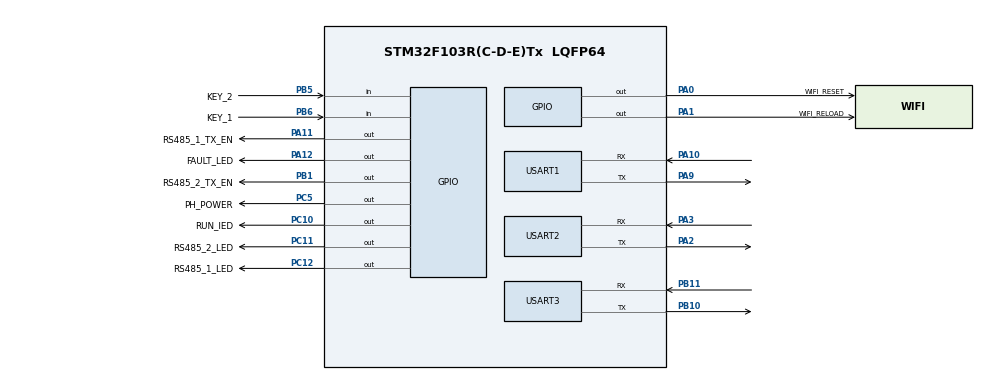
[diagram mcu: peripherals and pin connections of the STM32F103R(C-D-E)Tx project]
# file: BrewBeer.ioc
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Dma.Request0=USART1_RX
Dma.Request1=USART1_TX
Dma.Request2=USART3_RX
Dma.Request3=USART3_TX
Dma.Request4=USART2_RX
Dma.Request5=USART2_TX
Dma.USART1_RX.0.Direction=DMA_PERIPH_TO_MEMORY
Dma.USART1_RX.0.Instance=DMA1_Channel5
Dma.USART1_RX.0.MemDataAlignment=DMA_MDATAALIGN_BYTE
Dma.USART1_RX.0.MemInc=DMA_MINC_ENABLE
Dma.USART1_RX.0.Mode=DMA_NORMAL
Dma.USART1_RX.0.PeriphDataAlignment=DMA_PDATAALIGN_BYTE
Dma.USART1_RX.0.PeriphInc=DMA_PINC_DISABLE
Dma.USART1_RX.0.Priority=DMA_PRIORITY_HIGH
Dma.USART1_TX.1.Direction=DMA_MEMORY_TO_PERIPH
Dma.USART1_TX.1.Instance=DMA1_Channel4
Dma.USART1_TX.1.MemDataAlignment=DMA_MDATAALIGN_BYTE
Dma.USART1_TX.1.MemInc=DMA_MINC_ENABLE
Dma.USART1_TX.1.Mode=DMA_NORMAL
Dma.USART1_TX.1.PeriphDataAlignment=DMA_PDATAALIGN_BYTE
Dma.USART1_TX.1.PeriphInc=DMA_PINC_DISABLE
Dma.USART1_TX.1.Priority=DMA_PRIORITY_LOW
Dma.USART2_RX.4.Direction=DMA_PERIPH_TO_MEMORY
Dma.USART2_RX.4.Instance=DMA1_Channel6
Dma.USART2_RX.4.MemDataAlignment=DMA_MDATAALIGN_BYTE
Dma.USART2_RX.4.MemInc=DMA_MINC_ENABLE
Dma.USART2_RX.4.Mode=DMA_NORMAL
Dma.USART2_RX.4.PeriphDataAlignment=DMA_PDATAALIGN_BYTE
Dma.USART2_RX.4.PeriphInc=DMA_PINC_DISABLE
Dma.USART2_RX.4.Priority=DMA_PRIORITY_HIGH
Dma.USART2_TX.5.Direction=DMA_MEMORY_TO_PERIPH
Dma.USART2_TX.5.Instance=DMA1_Channel7
Dma.USART2_TX.5.MemDataAlignment=DMA_MDATAALIGN_BYTE
Dma.USART2_TX.5.MemInc=DMA_MINC_ENABLE
Dma.USART2_TX.5.Mode=DMA_NORMAL
Dma.USART2_TX.5.PeriphDataAlignment=DMA_PDATAALIGN_BYTE
Dma.USART2_TX.5.PeriphInc=DMA_PINC_DISABLE
Dma.USART2_TX.5.Priority=DMA_PRIORITY_LOW
Dma.USART3_RX.2.Direction=DMA_PERIPH_TO_MEMORY
Dma.USART3_RX.2.Instance=DMA1_Channel3
Dma.USART3_RX.2.MemDataAlignment=DMA_MDATAALIGN_BYTE
Dma.USART3_RX.2.MemInc=DMA_MINC_ENABLE
Dma.USART3_RX.2.Mode=DMA_NORMAL
Dma.USART3_RX.2.PeriphDataAlignment=DMA_PDATAALIGN_BYTE
Dma.USART3_RX.2.PeriphInc=DMA_PINC_DISABLE
Dma.USART3_RX.2.Priority=DMA_PRIORITY_HIGH
Dma.USART3_TX.3.Direction=DMA_MEMORY_TO_PERIPH
Dma.USART3_TX.3.Instance=DMA1_Channel2
Dma.USART3_TX.3.MemDataAlignment=DMA_MDATAALIGN_BYTE
Dma.USART3_TX.3.MemInc=DMA_MINC_ENABLE
Dma.USART3_TX.3.Mode=DMA_NORMAL
Dma.USART3_TX.3.PeriphDataAlignment=DMA_PDATAALIGN_BYTE
Dma.USART3_TX.3.PeriphInc=DMA_PINC_DISABLE
Dma.USART3_TX.3.Priority=DMA_PRIORITY_LOW
FREERTOS.INCLUDE_uxTaskGetStackHighWaterMark=1
FREERTOS.INCLUDE_xTaskGetCurrentTaskHandle=1
FREERTOS.Queues01=SerialQueue,5,uint32_t,NULL;KeyQueue,4,uint8_t,NULL;SysQueue,8,uint32_t,NULL
FREERTOS.Tasks01=System,0,200,SystemTask,Default;SerialServer,2,300,SerialServerTask,Default;ReadKey,0,128,ReadKeyTask,Default;DealKey,1,200,DealKeyTask,Default;Watcher,0,400,WatcherTask,Default
FREERTOS.configTOTAL_HEAP_SIZE=20480
FREERTOS.configUSE_IDLE_HOOK=1
FREERTOS.configUSE_TICK_HOOK=1
IWDG.Prescaler=IWDG_PRESCALER_64
Mcu.Family=STM32F1
Mcu.Name=STM32F103R(C-D-E)Tx
Mcu.Package=LQFP64
NVIC.DMA1_Channel2_IRQn=true\:5\:0\:true\:false\:true\:true
NVIC.DMA1_Channel3_IRQn=true\:5\:0\:false\:false\:true\:true
NVIC.DMA1_Channel4_IRQn=true\:5\:0\:false\:false\:true\:true
NVIC.DMA1_Channel5_IRQn=true\:5\:0\:false\:false\:true\:true
NVIC.DMA1_Channel6_IRQn=true\:5\:0\:false\:false\:true\:true
NVIC.DMA1_Channel7_IRQn=true\:5\:0\:false\:false\:true\:true
NVIC.PriorityGroup=NVIC_PRIORITYGROUP_4
NVIC.TIM1_UP_IRQn=true\:8\:0\:true\:false\:true\:true
NVIC.TIM2_IRQn=true\:8\:0\:true\:false\:true\:true
NVIC.TIM3_IRQn=true\:8\:0\:true\:false\:true\:true
NVIC.TIM4_IRQn=true\:8\:0\:true\:false\:true\:true
NVIC.TIM5_IRQn=true\:8\:0\:true\:false\:true\:true
NVIC.TIM6_IRQn=true\:8\:0\:true\:false\:true\:true
NVIC.TIM7_IRQn=true\:0\:0\:false\:false\:true\:false
NVIC.TimeBase=TIM7_IRQn
NVIC.TimeBaseIP=TIM7
NVIC.USART1_IRQn=true\:5\:0\:true\:false\:true\:true
NVIC.USART2_IRQn=true\:5\:0\:false\:false\:true\:true
NVIC.USART3_IRQn=true\:5\:0\:false\:false\:true\:true
PA0-WKUP.GPIO_Label=WIFI_RESET
PA0-WKUP.Signal=GPIO_Output
PA1.GPIO_Label=WIFI_RELOAD
PA1.Signal=GPIO_Output
PA10.Mode=Asynchronous
PA10.Signal=USART1_RX
PA11.GPIO_Label=RS485_1_TX_EN
PA11.Signal=GPIO_Output
PA12.GPIO_Label=FAULT_LED
PA12.Signal=GPIO_Output
PA13.Mode=Serial_Wire
PA13.Signal=SYS_JTMS-SWDIO
PA14.Mode=Serial_Wire
PA14.Signal=SYS_JTCK-SWCLK
PA2.Mode=Asynchronous
PA2.Signal=USART2_TX
PA3.Mode=Asynchronous
PA3.Signal=USART2_RX
PA9.Mode=Asynchronous
PA9.Signal=USART1_TX
PB1.GPIO_Label=RS485_2_TX_EN
PB1.Signal=GPIO_Output
PB10.Mode=Asynchronous
PB10.Signal=USART3_TX
PB11.Mode=Asynchronous
PB11.Signal=USART3_RX
PB5.GPIO_Label=KEY_2
PB5.Signal=GPIO_Input
PB6.GPIO_Label=KEY_1
PB6.Signal=GPIO_Input
PC10.GPIO_Label=RUN_IED
PC10.Signal=GPIO_Output
PC11.GPIO_Label=RS485_2_LED
PC11.Signal=GPIO_Output
PC12.GPIO_Label=RS485_1_LED
PC12.Signal=GPIO_Output
PC14-OSC32_IN.Mode=LSE-External-Oscillator
PC14-OSC32_IN.Signal=RCC_OSC32_IN
PC15-OSC32_OUT.Mode=LSE-External-Oscillator
PC15-OSC32_OUT.Signal=RCC_OSC32_OUT
PC5.GPIO_Label=PH_POWER
PC5.Signal=GPIO_Output
PD0-OSC_IN.Mode=HSE-External-Oscillator
PD0-OSC_IN.Signal=RCC_OSC_IN
PD1-OSC_OUT.Mode=HSE-External-Oscillator
PD1-OSC_OUT.Signal=RCC_OSC_OUT
ProjectManager.HeapSize=0x800
ProjectManager.StackSize=0x800
ProjectManager.TargetToolchain=MDK-ARM V5
RCC.AHBFreq_Value=72000000
RCC.APB1CLKDivider=RCC_HCLK_DIV2
RCC.APB1Freq_Value=36000000
RCC.APB1TimFreq_Value=72000000
RCC.APB2Freq_Value=72000000
RCC.APB2TimFreq_Value=72000000
RCC.HCLKFreq_Value=72000000
RCC.HSIState=RCC_HSI_ON
RCC.PLLMUL=RCC_PLL_MUL9
RCC.PLLSourceVirtual=RCC_PLLSOURCE_HSE
RCC.RTCClockSelection=RCC_RTCCLKSOURCE_LSE
RCC.SYSCLKFreq_VALUE=72000000
RCC.SYSCLKSource=RCC_SYSCLKSOURCE_PLLCLK
RCC.USBFreq_Value=72000000
TIM1.Period=999
TIM1.Prescaler=71
TIM2.Period=999
TIM2.Prescaler=71
TIM3.Period=999
TIM3.Prescaler=71
TIM4.Period=999
TIM4.Prescaler=71
TIM5.Period=999
TIM5.Prescaler=71
TIM6.Period=999
TIM6.Prescaler=71
VP_FREERTOS_VS_ENABLE.Mode=Enabled
VP_IWDG_VS_IWDG.Mode=IWDG_Activate
VP_RTC_No_RTC_Output.Mode=RTC_OUT_NO
VP_SYS_VS_tim7.Mode=TIM7
VP_TIM1_VS_ClockSourceINT.Mode=Internal
VP_TIM2_VS_ClockSourceINT.Mode=Internal
VP_TIM3_VS_ClockSourceINT.Mode=Internal
VP_TIM4_VS_ClockSourceINT.Mode=Internal
VP_TIM5_VS_ClockSourceINT.Mode=Internal
VP_TIM6_VS_ClockSourceINT.Mode=Enable_Timer
board=BrewBeer

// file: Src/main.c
/**
  ******************************************************************************
  * File Name          : main.c
  * Description        : Main program body
  ******************************************************************************
  *
  * COPYRIGHT(c) 2017 STMicroelectronics
  *
  * Redistribution and use in source and binary forms, with or without modification,
  * are permitted provided that the following conditions are met:
  *   1. Redistributions of source code must retain the above copyright notice,
  *      this list of conditions and the following disclaimer.
  *   2. Redistributions in binary form must reproduce the above copyright notice,
  *      this list of conditions and the following disclaimer in the documentation
  *      and/or other materials provided with the distribution.
  *   3. Neither the name of STMicroelectronics nor the names of its contributors
  *      may be used to endorse or promote products derived from this software
  *      without specific prior written permission.
  *
  * THIS SOFTWARE IS PROVIDED BY THE COPYRIGHT HOLDERS AND CONTRIBUTORS "AS IS"
  * AND ANY EXPRESS OR IMPLIED WARRANTIES, INCLUDING, BUT NOT LIMITED TO, THE
  * IMPLIED WARRANTIES OF MERCHANTABILITY AND FITNESS FOR A PARTICULAR PURPOSE ARE
  * DISCLAIMED. IN NO EVENT SHALL THE COPYRIGHT HOLDER OR CONTRIBUTORS BE LIABLE
  * FOR ANY DIRECT, INDIRECT, INCIDENTAL, SPECIAL, EXEMPLARY, OR CONSEQUENTIAL
  * DAMAGES (INCLUDING, BUT NOT LIMITED TO, PROCUREMENT OF SUBSTITUTE GOODS OR
  * SERVICES; LOSS OF USE, DATA, OR PROFITS; OR BUSINESS INTERRUPTION) HOWEVER
  * CAUSED AND ON ANY THEORY OF LIABILITY, WHETHER IN CONTRACT, STRICT LIABILITY,
  * OR TORT (INCLUDING NEGLIGENCE OR OTHERWISE) ARISING IN ANY WAY OUT OF THE USE
  * OF THIS SOFTWARE, EVEN IF ADVISED OF THE POSSIBILITY OF SUCH DAMAGE.
  *
  ******************************************************************************
  */
#include "stm32f1xx_hal.h"
#include "cmsis_os.h"
#include "dma.h"
#include "iwdg.h"
#include "rtc.h"
#include "tim.h"
#include "usart.h"
#include "gpio.h"

/* USER CODE BEGIN Includes */
#include "include.h"
/* USER CODE END Includes */

/* USER CODE BEGIN PV */
/* Private variables ---------------------------------------------------------*/

/* USER CODE END PV */

void SystemClock_Config(void);
void Error_Handler(void);
void MX_FREERTOS_Init(void);

/* USER CODE BEGIN PFP */
/* Private function prototypes -----------------------------------------------*/

/* USER CODE END PFP */

int main(void)
{

  /* USER CODE BEGIN 1 */

	start_app();
  while(1);
  /* USER CODE END 1 */

  /* MCU Configuration----------------------------------------------------------*/

  /* Reset of all peripherals, Initializes the Flash interface and the Systick. */
  HAL_Init();

  /* Configure the system clock */
  SystemClock_Config();

  /* Initialize all configured peripherals */
  MX_GPIO_Init();
  MX_DMA_Init();
  MX_RTC_Init();
  MX_USART1_UART_Init();
  MX_USART2_UART_Init();
  MX_IWDG_Init();
  MX_TIM1_Init();
  MX_TIM2_Init();
  MX_TIM3_Init();
  MX_TIM4_Init();
  MX_TIM5_Init();
  MX_TIM6_Init();
  MX_USART3_UART_Init();

  /* USER CODE BEGIN 2 */

  	PH_POWER_ON;
  	ENABLE_RS485_1_RX;
  	ENABLE_RS485_2_RX;

  	RELEASE_SMART_LINK;
  	RELEASE_WIFI_RESET;

	//SET_SMART_LINK;
	InitSoftTimer();
  	COM1LedBlink(500,0);
  	COM2LedBlink(400,0);
  	RuningLedBlink(300,0);
  	FaultLedBlink(100,0);
	SetAutoUpload(MachineInfo.UploadStepTime);//设置定时上传
	HAL_IWDG_Start(&hiwdg);
  /* USER CODE END 2 */

  /* Call init function for freertos objects (in freertos.c) */
  MX_FREERTOS_Init();

  /* Start scheduler */
  osKernelStart();

  /* We should never get here as control is now taken by the scheduler */

  /* Infinite loop */
  while (1)
  {

  }

}

/** System Clock Configuration
*/
void SystemClock_Config(void)
{

  RCC_OscInitTypeDef RCC_OscInitStruct;
  RCC_ClkInitTypeDef RCC_ClkInitStruct;
  RCC_PeriphCLKInitTypeDef PeriphClkInit;

  RCC_OscInitStruct.OscillatorType = RCC_OSCILLATORTYPE_LSI|RCC_OSCILLATORTYPE_HSE
                              |RCC_OSCILLATORTYPE_LSE;
  RCC_OscInitStruct.HSEState = RCC_HSE_ON;
  RCC_OscInitStruct.HSEPredivValue = RCC_HSE_PREDIV_DIV1;
  RCC_OscInitStruct.LSEState = RCC_LSE_ON;
  RCC_OscInitStruct.LSIState = RCC_LSI_ON;
  RCC_OscInitStruct.PLL.PLLState = RCC_PLL_ON;
  RCC_OscInitStruct.PLL.PLLSource = RCC_PLLSOURCE_HSE;
  RCC_OscInitStruct.PLL.PLLMUL = RCC_PLL_MUL9;
  if (HAL_RCC_OscConfig(&RCC_OscInitStruct) != HAL_OK)
  {
    Error_Handler();
  }

  RCC_ClkInitStruct.ClockType = RCC_CLOCKTYPE_HCLK|RCC_CLOCKTYPE_SYSCLK
                              |RCC_CLOCKTYPE_PCLK1|RCC_CLOCKTYPE_PCLK2;
  RCC_ClkInitStruct.SYSCLKSource = RCC_SYSCLKSOURCE_PLLCLK;
  RCC_ClkInitStruct.AHBCLKDivider = RCC_SYSCLK_DIV1;
  RCC_ClkInitStruct.APB1CLKDivider = RCC_HCLK_DIV2;
  RCC_ClkInitStruct.APB2CLKDivider = RCC_HCLK_DIV2;
  if (HAL_RCC_ClockConfig(&RCC_ClkInitStruct, FLASH_LATENCY_2) != HAL_OK)
  {
    Error_Handler();
  }

  PeriphClkInit.PeriphClockSelection = RCC_PERIPHCLK_RTC;
  PeriphClkInit.RTCClockSelection = RCC_RTCCLKSOURCE_LSE;
  if (HAL_RCCEx_PeriphCLKConfig(&PeriphClkInit) != HAL_OK)
  {
    Error_Handler();
  }

  HAL_SYSTICK_Config(HAL_RCC_GetHCLKFreq()/1000);

  HAL_SYSTICK_CLKSourceConfig(SYSTICK_CLKSOURCE_HCLK);

  /* SysTick_IRQn interrupt configuration */
  HAL_NVIC_SetPriority(SysTick_IRQn, 15, 0);
}

void HAL_TIM_PeriodElapsedCallback(TIM_HandleTypeDef *htim)
{
/* USER CODE BEGIN Callback 0 */
	BaseType_t xHigherPriorityTaskWoken;
	xHigherPriorityTaskWoken = pdFALSE;
	unsigned int SerialQueueData = 0;

	if (htim == &SOFTTIMER) {
		INC_COUNTER_TIMER();
  	}

	if (htim == &WIFITIMER) {
  	HAL_TIM_Base_Stop_IT(&WIFITIMER);
	if(WifiOperatData.DmaCNDTR==  WIFICOM.hdmarx->Instance->CNDTR)
		{
			HAL_UART_DMAStop(&WIFICOM);
			WifiOperatData.recv_data_length= SERIAL_RXBUFF_SIZE -WifiOperatData.DmaCNDTR;
			HAL_UART_Receive_DMA(&WIFICOM, WifiOperatData.Rx_data, SERIAL_RXBUFF_SIZE);
			SerialQueueData = WIFIMSG;
			COM1LedBlink(10,0);
			xQueueSendFromISR(SerialQueueHandle,&SerialQueueData,&xHigherPriorityTaskWoken);
		}
	else
		{
			HAL_TIM_Base_Start_IT(&WIFITIMER);
			WifiOperatData.DmaCNDTR=  WIFICOM.hdmarx->Instance->CNDTR;
		}
 	}

	if (htim == &RS485TIMER1) {
  	HAL_TIM_Base_Stop_IT(&RS485TIMER1);
	if(Rs485_1OperatData.DmaCNDTR==  RS485COM1.hdmarx->Instance->CNDTR)
		{
			HAL_UART_DMAStop(&RS485COM1);
			Rs485_1OperatData.recv_data_length= SERIAL_RXBUFF_SIZE -Rs485_1OperatData.DmaCNDTR;
			HAL_UART_Receive_DMA(&RS485COM1, Rs485_1OperatData.Rx_data, SERIAL_RXBUFF_SIZE);
			SerialQueueData = RS485_1MSG;
			COM1LedBlink(10,0);
			xQueueSendFromISR(SerialQueueHandle,&SerialQueueData,&xHigherPriorityTaskWoken);
		}
	else
		{
			HAL_TIM_Base_Start_IT(&RS485TIMER1);
			Rs485_1OperatData.DmaCNDTR=  RS485COM1.hdmarx->Instance->CNDTR;
		}
  	}

	if (htim == &RS485TIMER2) {
  	HAL_TIM_Base_Stop_IT(&RS485TIMER2);
	if(Rs485_2OperatData.DmaCNDTR==  RS485COM2.hdmarx->Instance->CNDTR)
		{
			HAL_UART_DMAStop(&RS485COM2);
			Rs485_2OperatData.recv_data_length= SERIAL_RXBUFF_SIZE -Rs485_2OperatData.DmaCNDTR;
			HAL_UART_Receive_DMA(&RS485COM2, Rs485_2OperatData.Rx_data, SERIAL_RXBUFF_SIZE);
			SerialQueueData = RS485_2MSG;
			//COM2LedBlink(10,0);
			xQueueSendFromISR(SerialQueueHandle,&SerialQueueData,&xHigherPriorityTaskWoken);
		}
	else
		{
			HAL_TIM_Base_Start_IT(&RS485TIMER2);
			Rs485_2OperatData.DmaCNDTR=  RS485COM2.hdmarx->Instance->CNDTR;
		}
  	}

/* USER CODE END Callback 0 */
  if (htim->Instance == TIM7) {
    HAL_IncTick();
  }
}

void Error_Handler(void)
{
  while(1)
  {
  }
}

/************************ (C) COPYRIGHT STMicroelectronics *****END OF FILE****/

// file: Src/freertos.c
/**
  ******************************************************************************
  * File Name          : freertos.c
  * Description        : Code for freertos applications
  ******************************************************************************
  *
  * COPYRIGHT(c) 2017 STMicroelectronics
  *
  * Redistribution and use in source and binary forms, with or without modification,
  * are permitted provided that the following conditions are met:
  *   1. Redistributions of source code must retain the above copyright notice,
  *      this list of conditions and the following disclaimer.
  *   2. Redistributions in binary form must reproduce the above copyright notice,
  *      this list of conditions and the following disclaimer in the documentation
  *      and/or other materials provided with the distribution.
  *   3. Neither the name of STMicroelectronics nor the names of its contributors
  *      may be used to endorse or promote products derived from this software
  *      without specific prior written permission.
  *
  * THIS SOFTWARE IS PROVIDED BY THE COPYRIGHT HOLDERS AND CONTRIBUTORS "AS IS"
  * AND ANY EXPRESS OR IMPLIED WARRANTIES, INCLUDING, BUT NOT LIMITED TO, THE
  * IMPLIED WARRANTIES OF MERCHANTABILITY AND FITNESS FOR A PARTICULAR PURPOSE ARE
  * DISCLAIMED. IN NO EVENT SHALL THE COPYRIGHT HOLDER OR CONTRIBUTORS BE LIABLE
  * FOR ANY DIRECT, INDIRECT, INCIDENTAL, SPECIAL, EXEMPLARY, OR CONSEQUENTIAL
  * DAMAGES (INCLUDING, BUT NOT LIMITED TO, PROCUREMENT OF SUBSTITUTE GOODS OR
  * SERVICES; LOSS OF USE, DATA, OR PROFITS; OR BUSINESS INTERRUPTION) HOWEVER
  * CAUSED AND ON ANY THEORY OF LIABILITY, WHETHER IN CONTRACT, STRICT LIABILITY,
  * OR TORT (INCLUDING NEGLIGENCE OR OTHERWISE) ARISING IN ANY WAY OUT OF THE USE
  * OF THIS SOFTWARE, EVEN IF ADVISED OF THE POSSIBILITY OF SUCH DAMAGE.
  *
  ******************************************************************************
  */

#include "FreeRTOS.h"
#include "task.h"
#include "cmsis_os.h"

/* USER CODE BEGIN Includes */
#include "include.h"
/* USER CODE END Includes */

osThreadId SystemHandle;
osThreadId SerialServerHandle;
osThreadId ReadKeyHandle;
osThreadId DealKeyHandle;
osThreadId WatcherHandle;
osMessageQId SerialQueueHandle;
osMessageQId KeyQueueHandle;
osMessageQId SysQueueHandle;

/* USER CODE BEGIN Variables */
osMessageQId flash_queueHandle;
/* USER CODE END Variables */

void SystemTask(void const * argument);
void SerialServerTask(void const * argument);
void ReadKeyTask(void const * argument);
void DealKeyTask(void const * argument);
void WatcherTask(void const * argument);

void MX_FREERTOS_Init(void); /* (MISRA C 2004 rule 8.1) */

/* Hook prototypes */
void vApplicationIdleHook(void);
void vApplicationTickHook(void);

/* Init FreeRTOS */

void MX_FREERTOS_Init(void) {

  /* Create the thread(s) */
  /* definition and creation of System */
  osThreadDef(System, SystemTask, osPriorityNormal, 0, 200);
  SystemHandle = osThreadCreate(osThread(System), NULL);

  /* definition and creation of SerialServer */
  osThreadDef(SerialServer, SerialServerTask, osPriorityHigh, 0, 300);
  SerialServerHandle = osThreadCreate(osThread(SerialServer), NULL);

  /* definition and creation of ReadKey */
  osThreadDef(ReadKey, ReadKeyTask, osPriorityNormal, 0, 128);
  ReadKeyHandle = osThreadCreate(osThread(ReadKey), NULL);

  /* definition and creation of DealKey */
  osThreadDef(DealKey, DealKeyTask, osPriorityAboveNormal, 0, 200);
  DealKeyHandle = osThreadCreate(osThread(DealKey), NULL);

  /* definition and creation of Watcher */
  osThreadDef(Watcher, WatcherTask, osPriorityNormal, 0, 400);
  WatcherHandle = osThreadCreate(osThread(Watcher), NULL);

  /* Create the queue(s) */
  /* definition and creation of SerialQueue */
  osMessageQDef(SerialQueue, 5, uint32_t);
  SerialQueueHandle = osMessageCreate(osMessageQ(SerialQueue), NULL);

  /* definition and creation of KeyQueue */
  osMessageQDef(KeyQueue, 4, uint8_t);
  KeyQueueHandle = osMessageCreate(osMessageQ(KeyQueue), NULL);

  /* definition and creation of SysQueue */
  osMessageQDef(SysQueue, 8, uint32_t);
  SysQueueHandle = osMessageCreate(osMessageQ(SysQueue), NULL);

  /* USER CODE BEGIN RTOS_QUEUES */
  /* add queues, ... */
  osMessageQDef(FashQueue, 8, uint32_t);
  flash_queueHandle = osMessageCreate(osMessageQ(FashQueue), NULL);
  /* USER CODE END RTOS_QUEUES */
}

/* SystemTask function */
void SystemTask(void const * argument)
{

  /* USER CODE BEGIN SystemTask */
	save_task_info();
	WifiComStartRecv();
	Rs485_1ComStartRecv();
	Rs485_2ComStartRecv();
	GetDeviceID(MachineInfo.DeviceID);
	RuningLedBlink(800,1);

	//COM2LedBlink(800,1);
	//COM1LedBlink(500,1);
  /* Infinite loop */
  for(;;)
  {
    osDelay(1);
  }
  /* USER CODE END SystemTask */
}

/* SerialServerTask function */
void SerialServerTask(void const * argument)
{
  /* USER CODE BEGIN SerialServerTask */
  	unsigned int RecvMsg = 0;
  	save_task_info();
	osDelay(1000);
  /* Infinite loop */
  for(;;)
  {
	xQueueReceive(SerialQueueHandle, &RecvMsg, portMAX_DELAY);
	switch(RecvMsg)
		{
			case WIFIMSG:
				DealWifiRecvData();
				break;
			case RS485_1MSG:
				DealRs485_1RecvData();
				break;

			case RS485_2MSG:
				DealRs485_2RecvData();
				break;

			default:
				break;
		}
  }
  /* USER CODE END SerialServerTask */
}

/* ReadKeyTask function */
void ReadKeyTask(void const * argument)
{
  /* USER CODE BEGIN ReadKeyTask */
  	save_task_info();
  /* Infinite loop */
  for(;;)
  {
	read_key();
	osDelay(35);
  }
  /* USER CODE END ReadKeyTask */
}

/* DealKeyTask function */
void DealKeyTask(void const * argument)
{
  /* USER CODE BEGIN DealKeyTask */
  	save_task_info();
	unsigned char recv_key_value;
  /* Infinite loop */
  for(;;)
  {
	xQueueReceive(KeyQueueHandle, &recv_key_value, portMAX_DELAY);
	deal_key_value(recv_key_value);
  }
  /* USER CODE END DealKeyTask */
}

/* WatcherTask function */
void WatcherTask(void const * argument)
{
  /* USER CODE BEGIN WatcherTask */
	save_task_info();
  /* Infinite loop */
  for(;;)
  {
	osDelay(200);
	HAL_IWDG_Refresh(&hiwdg);

	//UploadDataByRs485_1(&msg);
	//UploadDataByRs485_2(&msg);
  }
  /* USER CODE END WatcherTask */
}

/************************ (C) COPYRIGHT STMicroelectronics *****END OF FILE****/
